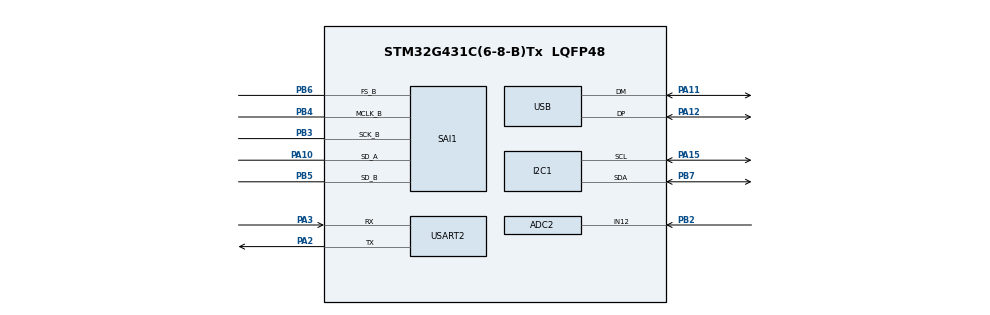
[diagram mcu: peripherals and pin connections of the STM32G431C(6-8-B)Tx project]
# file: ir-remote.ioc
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ADC2.Channel-0\#ChannelRegularConversion=ADC_CHANNEL_12
ADC2.NbrOfConversionFlag=1
ADC2.OffsetNumber-0\#ChannelRegularConversion=ADC_OFFSET_NONE
ADC2.Rank-0\#ChannelRegularConversion=1
ADC2.SamplingTime-0\#ChannelRegularConversion=ADC_SAMPLETIME_2CYCLES_5
Dma.ADC2.2.Direction=DMA_PERIPH_TO_MEMORY
Dma.ADC2.2.EventEnable=DISABLE
Dma.ADC2.2.Instance=DMA1_Channel3
Dma.ADC2.2.MemDataAlignment=DMA_MDATAALIGN_HALFWORD
Dma.ADC2.2.MemInc=DMA_MINC_ENABLE
Dma.ADC2.2.Mode=DMA_NORMAL
Dma.ADC2.2.PeriphDataAlignment=DMA_PDATAALIGN_HALFWORD
Dma.ADC2.2.PeriphInc=DMA_PINC_DISABLE
Dma.ADC2.2.Polarity=HAL_DMAMUX_REQ_GEN_RISING
Dma.ADC2.2.Priority=DMA_PRIORITY_LOW
Dma.ADC2.2.RequestNumber=1
Dma.ADC2.2.SignalID=NONE
Dma.ADC2.2.SyncEnable=DISABLE
Dma.ADC2.2.SyncPolarity=HAL_DMAMUX_SYNC_NO_EVENT
Dma.ADC2.2.SyncRequestNumber=1
Dma.ADC2.2.SyncSignalID=NONE
Dma.Request0=SAI1_A
Dma.Request1=SAI1_B
Dma.Request2=ADC2
Dma.SAI1_A.0.Direction=DMA_PERIPH_TO_MEMORY
Dma.SAI1_A.0.EventEnable=DISABLE
Dma.SAI1_A.0.Instance=DMA1_Channel1
Dma.SAI1_A.0.MemDataAlignment=DMA_MDATAALIGN_WORD
Dma.SAI1_A.0.MemInc=DMA_MINC_ENABLE
Dma.SAI1_A.0.Mode=DMA_CIRCULAR
Dma.SAI1_A.0.PeriphDataAlignment=DMA_PDATAALIGN_WORD
Dma.SAI1_A.0.PeriphInc=DMA_PINC_DISABLE
Dma.SAI1_A.0.Polarity=HAL_DMAMUX_REQ_GEN_RISING
Dma.SAI1_A.0.Priority=DMA_PRIORITY_HIGH
Dma.SAI1_A.0.RequestNumber=1
Dma.SAI1_A.0.SignalID=NONE
Dma.SAI1_A.0.SyncEnable=DISABLE
Dma.SAI1_A.0.SyncPolarity=HAL_DMAMUX_SYNC_NO_EVENT
Dma.SAI1_A.0.SyncRequestNumber=1
Dma.SAI1_A.0.SyncSignalID=NONE
Dma.SAI1_B.1.Direction=DMA_MEMORY_TO_PERIPH
Dma.SAI1_B.1.EventEnable=DISABLE
Dma.SAI1_B.1.Instance=DMA1_Channel2
Dma.SAI1_B.1.MemDataAlignment=DMA_MDATAALIGN_WORD
Dma.SAI1_B.1.MemInc=DMA_MINC_ENABLE
Dma.SAI1_B.1.Mode=DMA_NORMAL
Dma.SAI1_B.1.PeriphDataAlignment=DMA_PDATAALIGN_WORD
Dma.SAI1_B.1.PeriphInc=DMA_PINC_DISABLE
Dma.SAI1_B.1.Polarity=HAL_DMAMUX_REQ_GEN_RISING
Dma.SAI1_B.1.Priority=DMA_PRIORITY_HIGH
Dma.SAI1_B.1.RequestNumber=1
Dma.SAI1_B.1.SignalID=NONE
Dma.SAI1_B.1.SyncEnable=DISABLE
Dma.SAI1_B.1.SyncPolarity=HAL_DMAMUX_SYNC_NO_EVENT
Dma.SAI1_B.1.SyncRequestNumber=1
Dma.SAI1_B.1.SyncSignalID=NONE
I2C1.Timing=0x60715075
Mcu.Family=STM32G4
Mcu.Name=STM32G431C(6-8-B)Tx
Mcu.Package=LQFP48
NVIC.DMA1_Channel1_IRQn=true\:0\:0\:false\:false\:true\:false\:true\:true
NVIC.DMA1_Channel2_IRQn=true\:0\:0\:false\:false\:true\:false\:true\:true
NVIC.DMA1_Channel3_IRQn=true\:0\:0\:false\:false\:true\:false\:true\:true
NVIC.PriorityGroup=NVIC_PRIORITYGROUP_4
PA10.Mode=SAI_A_SyncSlave
PA10.Signal=SAI1_SD_A
PA11.Mode=Device
PA11.Signal=USB_DM
PA12.Mode=Device
PA12.Signal=USB_DP
PA13.Mode=Serial_Wire
PA13.Signal=SYS_JTMS-SWDIO
PA14.Mode=Serial_Wire
PA14.Signal=SYS_JTCK-SWCLK
PA15.Mode=I2C
PA15.Signal=I2C1_SCL
PA2.Mode=Asynchronous
PA2.Signal=USART2_TX
PA3.Mode=Asynchronous
PA3.Signal=USART2_RX
PB2.Mode=IN12-Single-Ended
PB2.Signal=ADC2_IN12
PB3.Mode=SAI_B_MasterWithClock
PB3.Signal=SAI1_SCK_B
PB4.Mode=SAI_B_MasterWithClock
PB4.Signal=SAI1_MCLK_B
PB5.Mode=SAI_B_MasterWithClock
PB5.Signal=SAI1_SD_B
PB6.Mode=SAI_B_MasterWithClock
PB6.Signal=SAI1_FS_B
PB7.Mode=I2C
PB7.Signal=I2C1_SDA
PF0-OSC_IN.Mode=HSE-External-Oscillator
PF0-OSC_IN.Signal=RCC_OSC_IN
PF1-OSC_OUT.Mode=HSE-External-Oscillator
PF1-OSC_OUT.Signal=RCC_OSC_OUT
ProjectManager.HeapSize=0x200
ProjectManager.StackSize=0x400
ProjectManager.TargetToolchain=CMake
RCC.ADC12Freq_Value=144000000
RCC.AHBFreq_Value=144000000
RCC.APB1Freq_Value=144000000
RCC.APB1TimFreq_Value=144000000
RCC.APB2Freq_Value=144000000
RCC.APB2TimFreq_Value=144000000
RCC.CK48CLockSelection=RCC_USBCLKSOURCE_HSI48
RCC.CortexFreq_Value=144000000
RCC.EXTERNAL_CLOCK_VALUE=12288000
RCC.HCLKFreq_Value=144000000
RCC.HSE_VALUE=16000000
RCC.HSI48_VALUE=48000000
RCC.HSI_VALUE=16000000
RCC.LSE_VALUE=32768
RCC.PLLM=RCC_PLLM_DIV6
RCC.PLLN=108
RCC.PLLQ=RCC_PLLQ_DIV6
RCC.PLLSourceVirtual=RCC_PLLSOURCE_HSE
RCC.SAI1CLockSelection=RCC_SAI1CLKSOURCE_PLL
RCC.SYSCLKFreq_VALUE=144000000
RCC.SYSCLKSource=RCC_SYSCLKSOURCE_PLLCLK
RCC.USBFreq_Value=48000000
RCC.VCOOutputFreq_Value=288000000
SAI1.AudioFrequency-SAI_B_MasterWithClock=SAI_AUDIO_FREQUENCY_48K
SAI1.BasicDataSize-SAI_B_MasterWithClock=SAI_PROTOCOL_DATASIZE_24BIT
SAI1.FIFOThreshold-SAI_B_MasterWithClock=SAI_FIFOTHRESHOLD_HF
SAI1.InitProtocol-SAI_A_SyncSlave=Enable
SAI1.InitProtocol-SAI_B_MasterWithClock=Enable
SAI1.Instance-SAI_A_SyncSlave=SAI$Index_Block_A
SAI1.Instance-SAI_B_MasterWithClock=SAI$Index_Block_B
SAI1.MckOutput-SAI_B_MasterWithClock=SAI_MCK_OUTPUT_ENABLE
SAI1.NoDivider-SAI_B_MasterWithClock=SAI_MASTERDIVIDER_ENABLE
SAI1.VirtualMode-SAI_A_SyncSlave=VM_SLAVE
SAI1.VirtualMode-SAI_B_MasterWithClock=VM_MASTER
SAI1.VirtualProtocol-SAI_A_BASIC=VM_BASIC_PROTOCOL
SAI1.VirtualProtocol-SAI_B_BASIC=VM_BASIC_PROTOCOL
USART2.VirtualMode-Asynchronous=VM_ASYNC
VP_SAI1_VP_$IpInstance_SAIA_SAI_BASIC.Mode=SAI_A_BASIC
VP_SAI1_VP_$IpInstance_SAIB_SAI_BASIC.Mode=SAI_B_BASIC
VP_SYS_VS_DBSignals.Mode=DisableDeadBatterySignals
board=custom

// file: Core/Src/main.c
/* USER CODE BEGIN Header */
/**
  ******************************************************************************
  * @file           : main.c
  * @brief          : Main program body
  ******************************************************************************
  * @attention
  *
  * Copyright (c) 2026 STMicroelectronics.
  * All rights reserved.
  *
  * This software is licensed under terms that can be found in the LICENSE file
  * in the root directory of this software component.
  * If no LICENSE file comes with this software, it is provided AS-IS.
  *
  ******************************************************************************
  */
/* USER CODE END Header */
#include "main.h"

ADC_HandleTypeDef hadc2;
DMA_HandleTypeDef hdma_adc2;

I2C_HandleTypeDef hi2c1;

SAI_HandleTypeDef hsai_BlockA1;
SAI_HandleTypeDef hsai_BlockB1;
DMA_HandleTypeDef hdma_sai1_a;
DMA_HandleTypeDef hdma_sai1_b;

UART_HandleTypeDef huart2;

PCD_HandleTypeDef hpcd_USB_FS;

void SystemClock_Config(void);
static void MX_GPIO_Init(void);
static void MX_DMA_Init(void);
static void MX_SAI1_Init(void);
static void MX_ADC2_Init(void);
static void MX_I2C1_Init(void);
static void MX_USART2_UART_Init(void);
static void MX_USB_PCD_Init(void);

int main(void)
{

  /* MCU Configuration--------------------------------------------------------*/

  /* Reset of all peripherals, Initializes the Flash interface and the Systick. */
  HAL_Init();

  /* Configure the system clock */
  SystemClock_Config();

  /* Initialize all configured peripherals */
  MX_GPIO_Init();
  MX_DMA_Init();
  MX_SAI1_Init();
  MX_ADC2_Init();
  MX_I2C1_Init();
  MX_USART2_UART_Init();
  MX_USB_PCD_Init();

  /* Infinite loop */
  while (1)
  {

  }
}

void SystemClock_Config(void)
{
  RCC_OscInitTypeDef RCC_OscInitStruct = {0};
  RCC_ClkInitTypeDef RCC_ClkInitStruct = {0};

  /** Configure the main internal regulator output voltage
  */
  HAL_PWREx_ControlVoltageScaling(PWR_REGULATOR_VOLTAGE_SCALE1_BOOST);

  /** Initializes the RCC Oscillators according to the specified parameters
  * in the RCC_OscInitTypeDef structure.
  */
  RCC_OscInitStruct.OscillatorType = RCC_OSCILLATORTYPE_HSI48|RCC_OSCILLATORTYPE_HSE;
  RCC_OscInitStruct.HSEState = RCC_HSE_ON;
  RCC_OscInitStruct.HSI48State = RCC_HSI48_ON;
  RCC_OscInitStruct.PLL.PLLState = RCC_PLL_ON;
  RCC_OscInitStruct.PLL.PLLSource = RCC_PLLSOURCE_HSE;
  RCC_OscInitStruct.PLL.PLLM = RCC_PLLM_DIV4;
  RCC_OscInitStruct.PLL.PLLN = 85;
  RCC_OscInitStruct.PLL.PLLP = RCC_PLLP_DIV2;
  RCC_OscInitStruct.PLL.PLLQ = RCC_PLLQ_DIV8;
  RCC_OscInitStruct.PLL.PLLR = RCC_PLLR_DIV2;
  if (HAL_RCC_OscConfig(&RCC_OscInitStruct) != HAL_OK)
  {
    Error_Handler();
  }

  /** Initializes the CPU, AHB and APB buses clocks
  */
  RCC_ClkInitStruct.ClockType = RCC_CLOCKTYPE_HCLK|RCC_CLOCKTYPE_SYSCLK
                              |RCC_CLOCKTYPE_PCLK1|RCC_CLOCKTYPE_PCLK2;
  RCC_ClkInitStruct.SYSCLKSource = RCC_SYSCLKSOURCE_PLLCLK;
  RCC_ClkInitStruct.AHBCLKDivider = RCC_SYSCLK_DIV1;
  RCC_ClkInitStruct.APB1CLKDivider = RCC_HCLK_DIV1;
  RCC_ClkInitStruct.APB2CLKDivider = RCC_HCLK_DIV1;

  if (HAL_RCC_ClockConfig(&RCC_ClkInitStruct, FLASH_LATENCY_4) != HAL_OK)
  {
    Error_Handler();
  }
}

static void MX_ADC2_Init(void)
{

  ADC_ChannelConfTypeDef sConfig = {0};

  /** Common config
  */
  hadc2.Instance = ADC2;
  hadc2.Init.ClockPrescaler = ADC_CLOCK_SYNC_PCLK_DIV4;
  hadc2.Init.Resolution = ADC_RESOLUTION_12B;
  hadc2.Init.DataAlign = ADC_DATAALIGN_RIGHT;
  hadc2.Init.GainCompensation = 0;
  hadc2.Init.ScanConvMode = ADC_SCAN_DISABLE;
  hadc2.Init.EOCSelection = ADC_EOC_SINGLE_CONV;
  hadc2.Init.LowPowerAutoWait = DISABLE;
  hadc2.Init.ContinuousConvMode = DISABLE;
  hadc2.Init.NbrOfConversion = 1;
  hadc2.Init.DiscontinuousConvMode = DISABLE;
  hadc2.Init.ExternalTrigConv = ADC_SOFTWARE_START;
  hadc2.Init.ExternalTrigConvEdge = ADC_EXTERNALTRIGCONVEDGE_NONE;
  hadc2.Init.DMAContinuousRequests = DISABLE;
  hadc2.Init.Overrun = ADC_OVR_DATA_PRESERVED;
  hadc2.Init.OversamplingMode = DISABLE;
  if (HAL_ADC_Init(&hadc2) != HAL_OK)
  {
    Error_Handler();
  }

  /** Configure Regular Channel
  */
  sConfig.Channel = ADC_CHANNEL_12;
  sConfig.Rank = ADC_REGULAR_RANK_1;
  sConfig.SamplingTime = ADC_SAMPLETIME_2CYCLES_5;
  sConfig.SingleDiff = ADC_SINGLE_ENDED;
  sConfig.OffsetNumber = ADC_OFFSET_NONE;
  sConfig.Offset = 0;
  if (HAL_ADC_ConfigChannel(&hadc2, &sConfig) != HAL_OK)
  {
    Error_Handler();
  }

}

static void MX_I2C1_Init(void)
{

  hi2c1.Instance = I2C1;
  hi2c1.Init.Timing = 0x40B285C2;
  hi2c1.Init.OwnAddress1 = 0;
  hi2c1.Init.AddressingMode = I2C_ADDRESSINGMODE_7BIT;
  hi2c1.Init.DualAddressMode = I2C_DUALADDRESS_DISABLE;
  hi2c1.Init.OwnAddress2 = 0;
  hi2c1.Init.OwnAddress2Masks = I2C_OA2_NOMASK;
  hi2c1.Init.GeneralCallMode = I2C_GENERALCALL_DISABLE;
  hi2c1.Init.NoStretchMode = I2C_NOSTRETCH_DISABLE;
  if (HAL_I2C_Init(&hi2c1) != HAL_OK)
  {
    Error_Handler();
  }

  /** Configure Analogue filter
  */
  if (HAL_I2CEx_ConfigAnalogFilter(&hi2c1, I2C_ANALOGFILTER_ENABLE) != HAL_OK)
  {
    Error_Handler();
  }

  /** Configure Digital filter
  */
  if (HAL_I2CEx_ConfigDigitalFilter(&hi2c1, 0) != HAL_OK)
  {
    Error_Handler();
  }

}

static void MX_SAI1_Init(void)
{

  hsai_BlockA1.Instance = SAI1_Block_A;
  hsai_BlockA1.Init.AudioMode = SAI_MODESLAVE_RX;
  hsai_BlockA1.Init.Synchro = SAI_SYNCHRONOUS;
  hsai_BlockA1.Init.OutputDrive = SAI_OUTPUTDRIVE_DISABLE;
  hsai_BlockA1.Init.FIFOThreshold = SAI_FIFOTHRESHOLD_EMPTY;
  hsai_BlockA1.Init.SynchroExt = SAI_SYNCEXT_DISABLE;
  hsai_BlockA1.Init.MonoStereoMode = SAI_STEREOMODE;
  hsai_BlockA1.Init.CompandingMode = SAI_NOCOMPANDING;
  hsai_BlockA1.Init.TriState = SAI_OUTPUT_NOTRELEASED;
  if (HAL_SAI_InitProtocol(&hsai_BlockA1, SAI_I2S_STANDARD, SAI_PROTOCOL_DATASIZE_16BIT, 2) != HAL_OK)
  {
    Error_Handler();
  }
  hsai_BlockB1.Instance = SAI1_Block_B;
  hsai_BlockB1.Init.AudioMode = SAI_MODEMASTER_TX;
  hsai_BlockB1.Init.Synchro = SAI_ASYNCHRONOUS;
  hsai_BlockB1.Init.OutputDrive = SAI_OUTPUTDRIVE_DISABLE;
  hsai_BlockB1.Init.NoDivider = SAI_MASTERDIVIDER_ENABLE;
  hsai_BlockB1.Init.MckOverSampling = SAI_MCK_OVERSAMPLING_DISABLE;
  hsai_BlockB1.Init.FIFOThreshold = SAI_FIFOTHRESHOLD_HF;
  hsai_BlockB1.Init.AudioFrequency = SAI_AUDIO_FREQUENCY_48K;
  hsai_BlockB1.Init.SynchroExt = SAI_SYNCEXT_DISABLE;
  hsai_BlockB1.Init.MonoStereoMode = SAI_STEREOMODE;
  hsai_BlockB1.Init.CompandingMode = SAI_NOCOMPANDING;
  hsai_BlockB1.Init.TriState = SAI_OUTPUT_NOTRELEASED;
  if (HAL_SAI_InitProtocol(&hsai_BlockB1, SAI_I2S_STANDARD, SAI_PROTOCOL_DATASIZE_24BIT, 2) != HAL_OK)
  {
    Error_Handler();
  }

}

static void MX_USART2_UART_Init(void)
{

  huart2.Instance = USART2;
  huart2.Init.BaudRate = 115200;
  huart2.Init.WordLength = UART_WORDLENGTH_8B;
  huart2.Init.StopBits = UART_STOPBITS_1;
  huart2.Init.Parity = UART_PARITY_NONE;
  huart2.Init.Mode = UART_MODE_TX_RX;
  huart2.Init.HwFlowCtl = UART_HWCONTROL_NONE;
  huart2.Init.OverSampling = UART_OVERSAMPLING_16;
  huart2.Init.OneBitSampling = UART_ONE_BIT_SAMPLE_DISABLE;
  huart2.Init.ClockPrescaler = UART_PRESCALER_DIV1;
  huart2.AdvancedInit.AdvFeatureInit = UART_ADVFEATURE_NO_INIT;
  if (HAL_UART_Init(&huart2) != HAL_OK)
  {
    Error_Handler();
  }
  if (HAL_UARTEx_SetTxFifoThreshold(&huart2, UART_TXFIFO_THRESHOLD_1_8) != HAL_OK)
  {
    Error_Handler();
  }
  if (HAL_UARTEx_SetRxFifoThreshold(&huart2, UART_RXFIFO_THRESHOLD_1_8) != HAL_OK)
  {
    Error_Handler();
  }
  if (HAL_UARTEx_DisableFifoMode(&huart2) != HAL_OK)
  {
    Error_Handler();
  }

}

static void MX_USB_PCD_Init(void)
{

  hpcd_USB_FS.Instance = USB;
  hpcd_USB_FS.Init.dev_endpoints = 8;
  hpcd_USB_FS.Init.speed = PCD_SPEED_FULL;
  hpcd_USB_FS.Init.phy_itface = PCD_PHY_EMBEDDED;
  hpcd_USB_FS.Init.Sof_enable = DISABLE;
  hpcd_USB_FS.Init.low_power_enable = DISABLE;
  hpcd_USB_FS.Init.lpm_enable = DISABLE;
  hpcd_USB_FS.Init.battery_charging_enable = DISABLE;
  if (HAL_PCD_Init(&hpcd_USB_FS) != HAL_OK)
  {
    Error_Handler();
  }

}

static void MX_DMA_Init(void)
{

  /* DMA controller clock enable */
  __HAL_RCC_DMAMUX1_CLK_ENABLE();
  __HAL_RCC_DMA1_CLK_ENABLE();

  /* DMA interrupt init */
  /* DMA1_Channel1_IRQn interrupt configuration */
  HAL_NVIC_SetPriority(DMA1_Channel1_IRQn, 0, 0);
  HAL_NVIC_EnableIRQ(DMA1_Channel1_IRQn);
  /* DMA1_Channel2_IRQn interrupt configuration */
  HAL_NVIC_SetPriority(DMA1_Channel2_IRQn, 0, 0);
  HAL_NVIC_EnableIRQ(DMA1_Channel2_IRQn);
  /* DMA1_Channel3_IRQn interrupt configuration */
  HAL_NVIC_SetPriority(DMA1_Channel3_IRQn, 0, 0);
  HAL_NVIC_EnableIRQ(DMA1_Channel3_IRQn);

}

static void MX_GPIO_Init(void)
{

  /* GPIO Ports Clock Enable */
  __HAL_RCC_GPIOF_CLK_ENABLE();
  __HAL_RCC_GPIOA_CLK_ENABLE();
  __HAL_RCC_GPIOB_CLK_ENABLE();

}

void Error_Handler(void)
{
  __disable_irq();
  while (1)
  {
  }
}
